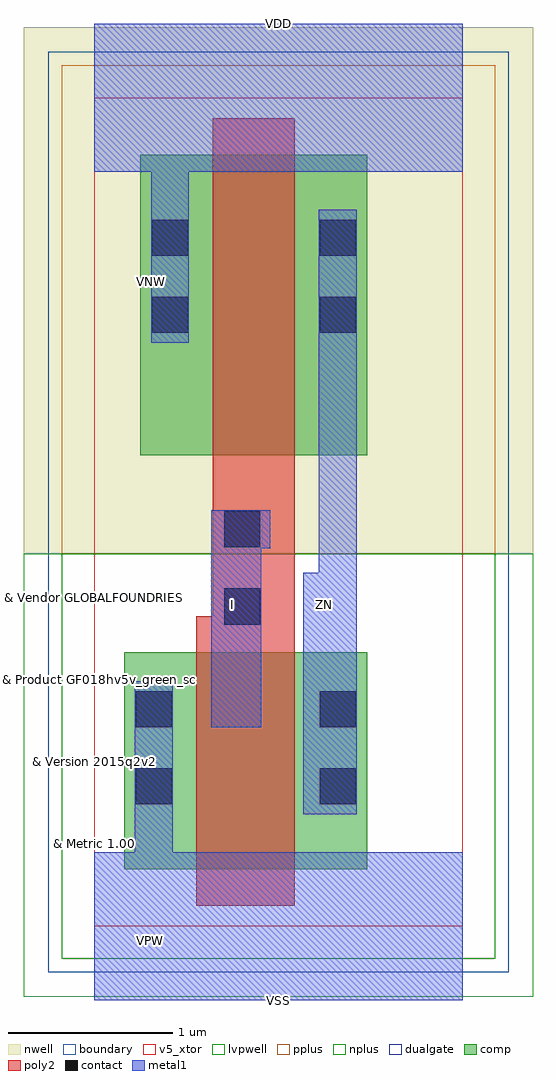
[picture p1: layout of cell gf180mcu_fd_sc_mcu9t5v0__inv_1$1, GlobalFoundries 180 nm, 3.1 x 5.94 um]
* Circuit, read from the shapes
.subckt gf180mcu_fd_sc_mcu9t5v0__inv_1$1 I VDD VNW VSS ZN
XM1 ZN I VSS VSUBS nfet_05v0 w=1.32u l=0.6u
XM2 ZN I VDD VNW pfet_05v0 w=1.83u l=0.5u
.ends

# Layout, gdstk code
import gdstk
lib = gdstk.Library(unit=1e-6, precision=1e-09)
def R(c, l, rs):  # rectangles x0, y0, x1, y1
    for r in rs: c.add(gdstk.rectangle(r[:2], r[2:], *l))
def P(c, l, *ps):  # polygons
    for p in ps: c.add(gdstk.Polygon(p, *l))
boundary = (0, 0)
nwell = (21, 0)
comp = (22, 0)
poly2 = (30, 0)
pplus = (31, 0)
nplus = (32, 0)
contact = (33, 0)
metal1 = (34, 0)
dualgate = (55, 0)
v5_xtor = (112, 1)
lvpwell = (204, 0)

gf180mcu_fd_sc_mcu9t5v0_ = lib.new_cell('gf180mcu_fd_sc_mcu9t5v0__inv_1$1')
R(gf180mcu_fd_sc_mcu9t5v0_, boundary, [(0,0,2.24,5.04)])
R(gf180mcu_fd_sc_mcu9t5v0_, nwell, [(-0.43,2.265,2.67,5.47)])
R(gf180mcu_fd_sc_mcu9t5v0_, comp, [(0.18,0.345,1.66,1.665), (0.28,2.865,1.66,4.695)])
P(gf180mcu_fd_sc_mcu9t5v0_, poly2, [(0.62,0.125),(0.62,1.885),(0.72,1.885),(0.72,4.915),(1.22,4.915),(1.22,0.125)])
R(gf180mcu_fd_sc_mcu9t5v0_, pplus, [(-0.2,2.265,2.44,5.24)])
R(gf180mcu_fd_sc_mcu9t5v0_, nplus, [(-0.2,-0.2,2.44,2.265)])
R(gf180mcu_fd_sc_mcu9t5v0_, contact, [(0.25,0.74,0.47,0.96), (1.37,0.74,1.59,0.96), (0.25,1.21,0.47,1.43), (1.37,1.21,1.59,1.43), (0.79,1.835,1.01,2.055), (0.79,2.305,1.01,2.525), (0.35,3.61,0.57,3.83), (1.37,3.61,1.59,3.83), (0.35,4.08,0.57,4.3), (1.37,4.08,1.59,4.3)])
P(gf180mcu_fd_sc_mcu9t5v0_, metal1, [(0.71,1.21),(0.71,2.53),(1.07,2.53),(1.07,2.3),(1.015,2.3),(1.015,1.21)],
  [(1.27,0.68),(1.27,2.15),(1.365,2.15),(1.365,4.36),(1.595,4.36),(1.595,0.68)],
  [(0,-0.45),(0,0.45),(0.245,0.45),(0.245,1.49),(0.475,1.49),(0.475,0.45),(2.24,0.45),(2.24,-0.45)],
  [(0.345,3.55),(0.345,4.59),(0,4.59),(0,5.49),(2.24,5.49),(2.24,4.59),(0.575,4.59),(0.575,3.55)])
R(gf180mcu_fd_sc_mcu9t5v0_, dualgate, [(-0.28,-0.28,2.52,5.32)])
R(gf180mcu_fd_sc_mcu9t5v0_, v5_xtor, [(0,0,2.24,5.04)])
R(gf180mcu_fd_sc_mcu9t5v0_, lvpwell, [(-0.43,-0.43,2.67,2.265)])
gf180mcu_fd_sc_mcu9t5v0_.add(gdstk.Label('I', (0.84,1.96), layer=34, texttype=10))
gf180mcu_fd_sc_mcu9t5v0_.add(gdstk.Label('VDD', (1.12,5.49), layer=34, texttype=10))
gf180mcu_fd_sc_mcu9t5v0_.add(gdstk.Label('VSS', (1.12,-0.45), layer=34, texttype=10))
gf180mcu_fd_sc_mcu9t5v0_.add(gdstk.Label('ZN', (1.4,1.96), layer=34, texttype=10))
gf180mcu_fd_sc_mcu9t5v0_.add(gdstk.Label('& Vendor GLOBALFOUNDRIES', (0,2), layer=63, texttype=63))
gf180mcu_fd_sc_mcu9t5v0_.add(gdstk.Label('& Product GF018hv5v_green_sc9', (0,1.5), layer=63, texttype=63))
gf180mcu_fd_sc_mcu9t5v0_.add(gdstk.Label('& Version 2015q2v2', (0,1), layer=63, texttype=63))
gf180mcu_fd_sc_mcu9t5v0_.add(gdstk.Label('& Metric 1.00', (0,0.5), layer=63, texttype=63))
gf180mcu_fd_sc_mcu9t5v0_.add(gdstk.Label('VNW', (0.345,3.92), layer=21, texttype=10))
gf180mcu_fd_sc_mcu9t5v0_.add(gdstk.Label('VPW', (0.34,-0.085), layer=204, texttype=10))

lib.write_gds('gf180mcu_fd_sc_mcu9t5v0__inv_1_1.gds')
